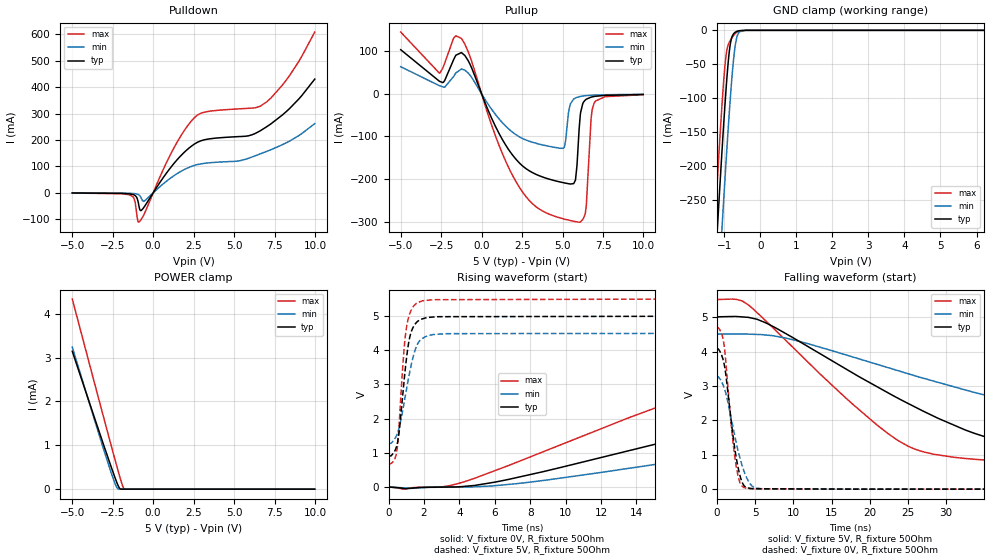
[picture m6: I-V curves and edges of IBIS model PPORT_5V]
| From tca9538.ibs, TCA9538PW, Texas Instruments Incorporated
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[Model]   PPORT_5V
Model_type   I/O
Polarity   Non-Inverting
Enable   Active-Low
Vinl = .8
Vinh = 2
Vmeas = 2.5
Vref = 5
Cref = 15pF
Rref = 50
|   typ   min   max
C_comp   2.446p   2.284p   2.721p
|C_comp (ON state)   2.718p   2.500p   2.993p
|C_comp (OFF state)   2.446p   2.284p   2.721p
[Voltage Range]   5   4.5   5.5
[Temperature Range]   27   125   -40
[Pullup Reference]   5   4.5   5.5
[Pulldown Reference]   -0   -0   -0
[Power Clamp Reference]   5   4.5   5.5
[GND Clamp Reference]   -0   -0   -0
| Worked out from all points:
|   slope of the pulldown table from 0 to 0.75 V, typ, clamps not added: 10.9 ohm
|   slope of the pullup table from 0 to 0.75 V, typ, clamps not added: 11.1 ohm
|   GND clamp passes 1 mA (typ) near -0.62 V on its own axis
|   POWER clamp passes 1 mA (typ) near -3.05 V on its own axis
|   falling waveform, V_fixture 5V, R_fixture 50Ohm: 20-80 % time 20.8ns typ, 34.9ns min, 14.2ns max; typ from 5 V to 0.907 V
|   rising waveform, V_fixture 0V, R_fixture 50Ohm: 20-80 % time 22.9ns typ, 33.1ns min, 15.5ns max; typ from 0 V to 4.08 V
|   rising waveform, V_fixture 5V, R_fixture 50Ohm: 20-80 % time 503ps typ, 732ps min, 403ps max; typ from 0.907 V to 5 V
|   falling waveform, V_fixture 0V, R_fixture 50Ohm: 20-80 % time 1.4ns typ, 2ns min, 1.2ns max; typ from 4.08 V to 0 V
[Pulldown]
|   Voltage   I(typ)   I(min)   I(max)
-5V       -470.9uA   -234.2uA   -696.9uA
-1.475V   -3.768mA   -1.595mA   -7.022mA
-1.175V   -8.101mA   -2.788mA   -22.63mA
-950mV    -28.83mA   -5.671mA   -105.8mA
-875mV    -51.18mA   -8.117mA   -110.4mA
-560mV    -53.43mA   -31.26mA   -80.74mA
1.06V     94.1mA     55.1mA     143.9mA
2.53V     183.8mA    103.4mA    283.4mA
5.89V     215.7mA    130.7mA    319.7mA
7.015V    250mA      156.8mA    344mA
8.425V    318.6mA    195.6mA    443.3mA
9.985V    430mA      261.8mA    607.9mA
[GND Clamp]
|   Voltage   I(typ)   I(min)   I(max)
-5V       -4.032A    -4.137A    -3.968A
-1.43V    -516mA     -631.9mA   -443.5mA
-1.25V    -346.9mA   -462.9mA   -274.4mA
-1.145V   -250.9mA   -366.2mA   -179.5mA
-1.055V   -171.7mA   -285.2mA   -104mA
-950mV    -87.03mA   -194.1mA   -37.23mA
-845mV    -25.16mA   -110mA     -16.03mA
-740mV    -5.059mA   -42.03mA   -7.486mA
-695mV    -2.838mA   -22.42mA   -4.772mA
-635mV    -1.252mA   -7.629mA   -2.171mA
-410mV    -15.51uA   -41.53uA   -16.84uA
9.985V    0A         0A         0A
[Pullup]
|   Voltage   I(typ)   I(min)   I(max)
-5V       103.7mA    63.72mA    145mA
-2.615V   29.81mA    19.34mA    48.82mA
-1.25V    96.93mA    58.35mA    130.3mA
2.11V     -152.9mA   -95.52mA   -205.1mA
5.095V    -208.8mA   -126mA     -293.7mA
5.47V     -211.5mA   -25.43mA   -297.1mA
5.8V      -202.1mA   -9.643mA   -299.8mA
6.1V      -48.56mA   -6.016mA   -300.7mA
6.4V      -14.63mA   -4.347mA   -282mA
6.76V     -7.71mA    -3.253mA   -61.25mA
6.955V    -6.119mA   -2.86mA    -21.71mA
9.985V    -1.434mA   -987.9uA   -1.885mA
[POWER Clamp]
|   Voltage   I(typ)   I(min)   I(max)
-5V       3.145mA    3.239mA    4.336mA
-3.155V   1.111mA    1.02mA     1.766mA
-2.435V   340.2uA    203.6uA    777uA
-2.255V   160.6uA    45.52uA    534.4uA
-2.18V    92.59uA    11.44uA    434.8uA
-2.09V    27.26uA    1.016uA    317.1uA
-1.91V    25.32nA    0A         97.31uA
-1.805V   0A         0A         11.02uA
9.985V    0A         0A         0A
[Ramp]
R_load = 50
|   typ   min   max
dV/dt_r   2.4462/2.29005e-08   1.96136/3.29329e-08   2.81437/1.55072e-08
dV/dt_f   2.45563/2.07876e-08   1.93432/3.4785e-08   2.88999/1.41631e-08
[Falling Waveform]
V_fixture = 5V
V_fixture_min = 4.5V
V_fixture_max = 5.5V
R_fixture = 50Ohm
C_fixture = 0F
|   Time   V(typ)   V(min)   V(max)
0s        5V         4.5V       5.5V
4.034ns   5V         4.511V     5.371V
9.858ns   4.417V     4.351V     4.141V
23.4ns    2.679V     3.467V     1.458V
31.09ns   1.855V     2.974V     925.1mV
37.67ns   1.383V     2.595V     815.7mV
44.47ns   1.183V     2.25V      764.6mV
56.56ns   1.044V     1.792V     725.2mV
72.13ns   972.9mV    1.529V     703.8mV
199.9ns   907.3mV    1.276V     683.4mV
[Rising Waveform]
V_fixture = 0V
V_fixture_min = 0V
V_fixture_max = 0V
R_fixture = 50Ohm
C_fixture = 0F
|   Time   V(typ)   V(min)   V(max)
0s        1.33uV     1.592uV    1.3uV
4.034ns   7.647mV    -74.3uV    116.7mV
16.78ns   1.472V     792.1mV    2.642V
23.59ns   2.267V     1.305V     3.728V
28.44ns   2.756V     1.634V     4.194V
34.09ns   3.23V      1.977V     4.414V
42ns      3.631V     2.38V      4.54V
53.61ns   3.85V      2.79V      4.617V
77.61ns   4.003V     3.105V     4.668V
199.9ns   4.077V     3.269V     4.691V
[Rising Waveform]
V_fixture = 5V
V_fixture_min = 4.5V
V_fixture_max = 5.5V
R_fixture = 50Ohm
C_fixture = 0F
|   Time   V(typ)   V(min)   V(max)
0s        907.3mV    1.276V     683.4mV
330.5ps   1.032V     1.397V     800.3mV
487.5ps   1.269V     1.556V     1.133V
642.4ps   1.837V     1.835V     2.225V
885ps     3.159V     2.492V     4.099V
1.134ns   4.222V     3.21V      4.969V
1.313ns   4.588V     3.653V     5.209V
1.631ns   4.844V     4.18V      5.394V
2.499ns   4.974V     4.459V     5.48V
199.9ns   5V         4.5V       5.5V
[Falling Waveform]
|Gnd
V_fixture = 0V
V_fixture_min = 0V
V_fixture_max = 0V
R_fixture = 50Ohm
C_fixture = 0F
|   Time   V(typ)   V(min)   V(max)
0s        4.077V     3.269V     4.691V
532.5ps   3.939V     3.154V     4.562V
923.6ps   3.648V     2.949V     4.195V
2.037ns   1.646V     1.855V     1.481V
2.672ns   720.7mV    1.197V     466mV
3.314ns   186.5mV    665mV      81.52mV
4.034ns   35.87mV    264.5mV    19.74mV
4.711ns   13.59mV    68.42mV    13.98mV
6.217ns   10.45mV    8.785mV    11.85mV
199.9ns   1.33uV     1.592uV    1.3uV
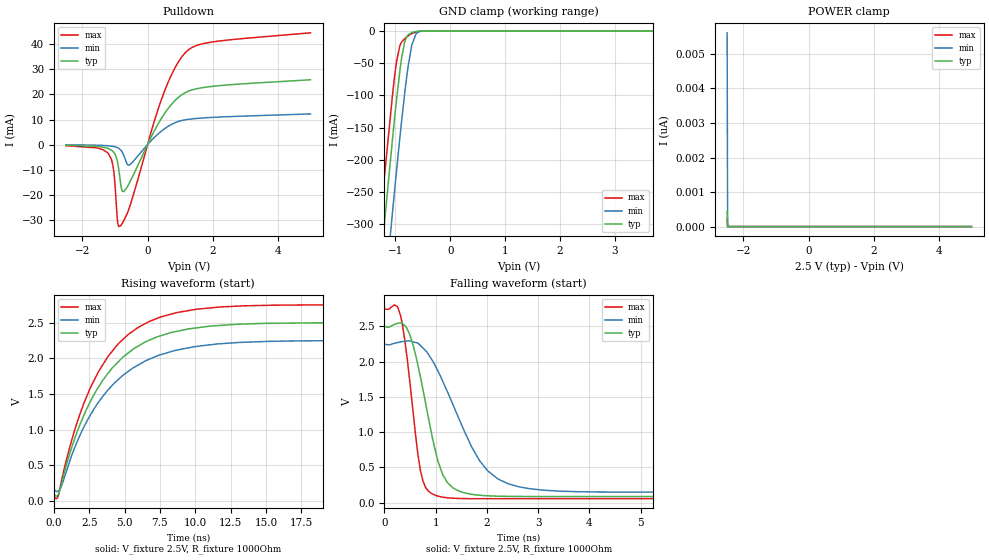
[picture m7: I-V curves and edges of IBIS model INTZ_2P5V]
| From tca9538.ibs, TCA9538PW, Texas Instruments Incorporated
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[Model]   INTZ_2P5V
Model_type   Open_drain
Polarity   Non-Inverting
Vmeas = 1.25
Vref = 2.5
Cref = 15pF
Rref = 1000
|   typ   min   max
|   (nom PVT)   (slow PVT)   (fast PVT)
C_comp   1.575p   1.499p   1.696p
|C_comp (ON state)   1.575p   1.499p   1.696p
|C_comp (OFF state)   1.578p   1.497p   1.752p
| Where   nom PVT is  Nominal Process, 2.5V, 27C
|   Fast PVT is Strong Process, 2.75V, -40C
|   Slow PVT is Weak Process, 2.25V, 125C
[Voltage Range]   2.5   2.25   2.75
[Temperature Range]   27   125   -40
[Pullup Reference]   2.5   2.25   2.75
[Pulldown Reference]   -0   -0   -0
[Power Clamp Reference]   2.5   2.25   2.75
[GND Clamp Reference]   -0   -0   -0
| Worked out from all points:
|   slope of the pulldown table from 0 to 0.375 V, typ, clamps not added: 39.9 ohm
|   GND clamp passes 1 mA (typ) near -0.63 V on its own axis
|   falling waveform, V_fixture 2.5V, R_fixture 1000Ohm: 20-80 % time 421ps typ, 816ps min, 259ps max; typ from 2.5 V to 0.086 V
|   rising waveform, V_fixture 2.5V, R_fixture 1000Ohm: 20-80 % time 3.9ns typ, 4.2ns min, 3.68ns max; typ from 0.086 V to 2.5 V
[Pulldown]
|   Voltage   I(typ)   I(min)   I(max)
-2.5V     -289.2uA   -109.1uA   -480.5uA
-1.202V   -1.599mA   -499.5uA   -3.587mA
-1.038V   -3.119mA   -792.1uA   -10.62mA
-917.5mV  -7.221mA   -1.279mA   -31.03mA
-820mV    -16.26mA   -2.218mA   -32.36mA
-730mV    -18.81mA   -4.369mA   -30.37mA
-580mV    -15.92mA   -8.273mA   -25.99mA
425mV     10.47mA    5.372mA    18mA
845mV     17.65mA    8.732mA    30.77mA
1.16V     20.77mA    9.893mA    36.77mA
2V        23.26mA    10.85mA    40.99mA
4.992V    25.87mA    12.22mA    44.62mA
[GND Clamp]
|   Voltage   I(typ)   I(min)   I(max)
-2.5V     -1.556A    -1.668A    -1.487A
-1.48V    -563.1mA   -678.8mA   -490.7mA
-1.27V    -364.7mA   -480.8mA   -291.9mA
-1.218V   -316mA     -432mA     -243.5mA
-1.052V   -168.3mA   -281.9mA   -99.91mA
-977.5mV  -106.2mA   -216.3mA   -47.26mA
-917.5mV  -62.02mA   -165.7mA   -22.82mA
-835mV    -18.97mA   -100.8mA   -12.23mA
-700mV    -2.355mA   -21.83mA   -3.998mA
-617.5mV  -734.2uA   -4.067mA   -1.273mA
-482.5mV  -59.66uA   -155.5uA   -77.67uA
4.992V    0A         0A         0A
[POWER Clamp]
|   Voltage   I(typ)   I(min)   I(max)
-2.5V     429.4pA    5.612nA    215pA
-2.485V   0A         0A         0A
-2.478V   0A         0A         0A
4.992V    0A         0A         0A
[Ramp]
R_load = 1000
|   typ   min   max
dV/dt_r   1.44864/3.89982e-09   1.26143/4.20065e-09   1.61739/3.67756e-09
dV/dt_f   1.44864/4.20872e-10   1.26143/8.15745e-10   1.61739/2.58527e-10
[Falling Waveform]
V_fixture = 2.5V
V_fixture_min = 2.25V
V_fixture_max = 2.75V
R_fixture = 1000Ohm
C_fixture = 0F
|   Time   V(typ)   V(min)   V(max)
0s        2.5V       2.25V      2.75V
317.3ps   2.549V     2.279V     2.651V
542.8ps   2.28V      2.284V     1.407V
754.7ps   1.597V     2.191V     301mV
1.045ns   587.7mV    1.866V     91.46mV
1.371ns   195.2mV    1.335V     59.57mV
1.857ns   103.8mV    595.2mV    54.34mV
2.215ns   90.04mV    335.1mV    54.22mV
3.778ns   85.41mV    153.3mV    54.23mV
99.9ns    85.6mV     147.6mV    54.35mV
[Rising Waveform]
V_fixture = 2.5V
V_fixture_min = 2.25V
V_fixture_max = 2.75V
R_fixture = 1000Ohm
C_fixture = 0F
|   Time   V(typ)   V(min)   V(max)
0s        85.6mV     147.6mV    54.35mV
317.3ps   92.11mV    142.3mV    74.64mV
1.158ns   684mV      578.4mV    779.2mV
2.215ns   1.244V     1.073V     1.416V
3.869ns   1.8V       1.566V     2.038V
5.274ns   2.078V     1.82V      2.338V
6.68ns    2.249V     1.983V     2.512V
10.11ns   2.429V     2.169V     2.69V
21.28ns   2.499V     2.25V      2.749V
99.9ns    2.5V       2.25V      2.75V
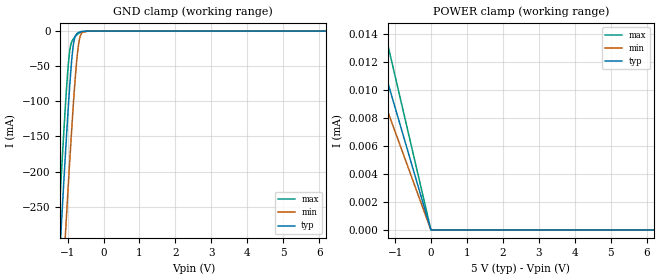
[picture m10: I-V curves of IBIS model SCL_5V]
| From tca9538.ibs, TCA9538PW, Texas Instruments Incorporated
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[Model]   SCL_5V
Model_type   Input
Vinl = .8
Vinh = 2
|   typ   min   max
|   (nom PVT)   (slow PVT)   (fast PVT)
C_comp   1.351p   1.281p   1.458p
| Where   nom PVT is  Nominal Process, 5.0V, 27C
|   Fast PVT is Strong Process, 5.5V, -40C
|   Slow PVT is Weak Process, 4.5V, 125C
[Voltage Range]   5   4.5   5.5
[Temperature Range]   27   125   -40
[Power Clamp Reference]   5   4.5   5.5
[GND Clamp Reference]   -0   -0   -0
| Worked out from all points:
|   GND clamp passes 1 mA (typ) near -0.65 V on its own axis
[GND Clamp]
|   Voltage   I(typ)   I(min)   I(max)
-5V       -4.031A    -4.136A    -3.967A
-1.43V    -515.1mA   -631mA     -442.5mA
-1.25V    -345.6mA   -461.8mA   -272.8mA
-1.145V   -249.3mA   -364.9mA   -177.4mA
-1.055V   -169.7mA   -283.6mA   -100.8mA
-950mV    -84.07mA   -192.1mA   -31.42mA
-845mV    -21.13mA   -107.3mA   -11.47mA
-740mV    -3.447mA   -38.39mA   -5.227mA
-665mV    -1.279mA   -10.35mA   -2.261mA
-590mV    -403.7uA   -1.765mA   -674.5uA
-425mV    -17.82uA   -36.75uA   -21.02uA
9.985V    0A         0A         0A
[POWER Clamp]
|   Voltage   I(typ)   I(min)   I(max)
-5V       2.3mA      2.359mA    3.166mA
-2.015V   20.15uA    14.31uA    181.3uA
-1.775V   15.57uA    12.53uA    21.92uA
-1.25V    10.96uA    8.81uA     13.77uA
-20mV     140nA      107.9nA    186.6nA
-5mV      8.08nA     71.96nA    20.98nA
25mV      0A         0A         0A
9.985V    0A         0A         0A
